VERSION 5.7 ;
  NOWIREEXTENSIONATPIN ON ;
  DIVIDERCHAR "/" ;
  BUSBITCHARS "[]" ;
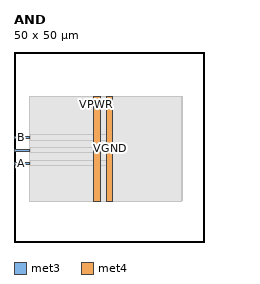
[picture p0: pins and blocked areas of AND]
MACRO AND
  CLASS BLOCK ;
  FOREIGN AND ;
  ORIGIN 0.000 0.000 ;
  SIZE 50.000 BY 50.000 ;
  PIN A
    DIRECTION INPUT ;
    USE SIGNAL ;
    ANTENNAGATEAREA 0.196500 ;
    PORT
      LAYER met3 ;
        RECT 0.000 20.440 4.000 21.040 ;
    END
  END A
  PIN B
    DIRECTION INPUT ;
    USE SIGNAL ;
    ANTENNAGATEAREA 0.196500 ;
    PORT
      LAYER met3 ;
        RECT 0.000 27.240 4.000 27.840 ;
    END
  END B
  PIN OUTPUT
    DIRECTION OUTPUT ;
    USE SIGNAL ;
    ANTENNADIFFAREA 0.445500 ;
    PORT
      LAYER met3 ;
        RECT 0.000 23.840 4.000 24.440 ;
    END
  END OUTPUT
  PIN VGND
    DIRECTION INOUT ;
    USE GROUND ;
    PORT
      LAYER met4 ;
        RECT 24.340 10.640 25.940 38.320 ;
    END
  END VGND
  PIN VPWR
    DIRECTION INOUT ;
    USE POWER ;
    PORT
      LAYER met4 ;
        RECT 21.040 10.640 22.640 38.320 ;
    END
  END VPWR
  OBS
      LAYER nwell ;
        RECT 5.330 10.795 44.350 38.165 ;
      LAYER li1 ;
        RECT 5.520 10.795 44.160 38.165 ;
      LAYER met1 ;
        RECT 4.210 10.640 44.160 38.320 ;
      LAYER met2 ;
        RECT 4.230 10.695 25.910 38.265 ;
      LAYER met3 ;
        RECT 3.990 28.240 25.930 38.245 ;
        RECT 4.400 26.840 25.930 28.240 ;
        RECT 3.990 24.840 25.930 26.840 ;
        RECT 4.400 23.440 25.930 24.840 ;
        RECT 3.990 21.440 25.930 23.440 ;
        RECT 4.400 20.040 25.930 21.440 ;
        RECT 3.990 10.715 25.930 20.040 ;
  END
END AND
END LIBRARY

